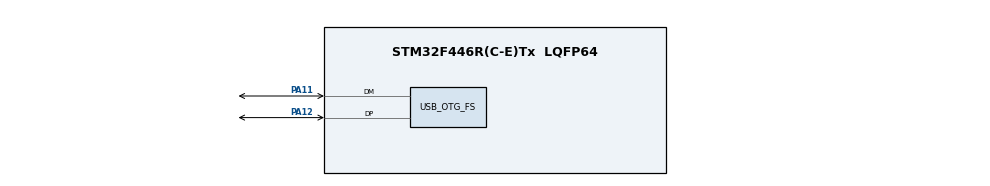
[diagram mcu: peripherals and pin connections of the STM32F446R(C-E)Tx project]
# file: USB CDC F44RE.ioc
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Mcu.Family=STM32F4
Mcu.Name=STM32F446R(C-E)Tx
Mcu.Package=LQFP64
NVIC.OTG_FS_IRQn=true\:0\:0\:false\:false\:true\:false\:true\:true
NVIC.PriorityGroup=NVIC_PRIORITYGROUP_4
NVIC.RCC_IRQn=true\:0\:0\:false\:false\:true\:true\:false\:true
PA11.Mode=Device_Only
PA11.Signal=USB_OTG_FS_DM
PA12.Mode=Device_Only
PA12.Signal=USB_OTG_FS_DP
PC14-OSC32_IN.Mode=LSE-External-Oscillator
PC14-OSC32_IN.Signal=RCC_OSC32_IN
PC15-OSC32_OUT.Mode=LSE-External-Oscillator
PC15-OSC32_OUT.Signal=RCC_OSC32_OUT
PH0-OSC_IN.Mode=HSE-External-Oscillator
PH0-OSC_IN.Signal=RCC_OSC_IN
PH1-OSC_OUT.Mode=HSE-External-Oscillator
PH1-OSC_OUT.Signal=RCC_OSC_OUT
ProjectManager.HeapSize=0x200
ProjectManager.StackSize=0x400
ProjectManager.TargetToolchain=STM32CubeIDE
RCC.AHBFreq_Value=72000000
RCC.APB1CLKDivider=RCC_HCLK_DIV2
RCC.APB1Freq_Value=36000000
RCC.APB1TimFreq_Value=72000000
RCC.APB2Freq_Value=72000000
RCC.APB2TimFreq_Value=72000000
RCC.CortexFreq_Value=72000000
RCC.HCLKFreq_Value=72000000
RCC.HSE_VALUE=8000000
RCC.PLLM=4
RCC.PLLN=72
RCC.PLLQ=3
RCC.SYSCLKFreq_VALUE=72000000
RCC.SYSCLKSource=RCC_SYSCLKSOURCE_PLLCLK
RCC.USBFreq_Value=48000000
RCC.VCOOutputFreq_Value=144000000
USB_DEVICE.CLASS_NAME_FS=CDC
USB_DEVICE.VirtualMode-CDC_FS=Cdc
USB_DEVICE.VirtualModeFS=Cdc_FS
USB_OTG_FS.VirtualMode=Device_Only
VP_USB_DEVICE_VS_USB_DEVICE_CDC_FS.Mode=CDC_FS
board=custom

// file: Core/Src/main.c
/* USER CODE BEGIN Header */
/**
  ******************************************************************************
  * @file           : main.c
  * @brief          : Main program body
  ******************************************************************************
  * @attention
  *
  * Copyright (c) 2023 STMicroelectronics.
  * All rights reserved.
  *
  * This software is licensed under terms that can be found in the LICENSE file
  * in the root directory of this software component.
  * If no LICENSE file comes with this software, it is provided AS-IS.
  *
  ******************************************************************************
  */
/* USER CODE END Header */
#include "main.h"
#include "usb_device.h"

/* USER CODE BEGIN Includes */
#include "usbd_cdc_if.h"
/* USER CODE END Includes */

/* USER CODE BEGIN PV */
	uint16_t uresult=0;
/* USER CODE END PV */

void SystemClock_Config(void);
static void MX_GPIO_Init(void);

int main(void)
{
  /* USER CODE BEGIN 1 */
	char *msg = "\nHello Duta'h";
  /* USER CODE END 1 */

  /* MCU Configuration--------------------------------------------------------*/

  /* Reset of all peripherals, Initializes the Flash interface and the Systick. */
  HAL_Init();

  /* Configure the system clock */
  SystemClock_Config();

  /* Initialize all configured peripherals */
  MX_GPIO_Init();
  MX_USB_DEVICE_Init();

  /* Infinite loop */
  /* USER CODE BEGIN WHILE */
  while (1)
  {
	  uresult = CDC_Transmit_FS(msg, strlen(msg));
	  HAL_Delay(1000);
    /* USER CODE END WHILE */

  }
}

void SystemClock_Config(void)
{
  RCC_OscInitTypeDef RCC_OscInitStruct = {0};
  RCC_ClkInitTypeDef RCC_ClkInitStruct = {0};

  /** Configure the main internal regulator output voltage
  */
  __HAL_RCC_PWR_CLK_ENABLE();
  __HAL_PWR_VOLTAGESCALING_CONFIG(PWR_REGULATOR_VOLTAGE_SCALE1);

  /** Initializes the RCC Oscillators according to the specified parameters
  * in the RCC_OscInitTypeDef structure.
  */
  RCC_OscInitStruct.OscillatorType = RCC_OSCILLATORTYPE_HSE;
  RCC_OscInitStruct.HSEState = RCC_HSE_ON;
  RCC_OscInitStruct.PLL.PLLState = RCC_PLL_ON;
  RCC_OscInitStruct.PLL.PLLSource = RCC_PLLSOURCE_HSE;
  RCC_OscInitStruct.PLL.PLLM = 4;
  RCC_OscInitStruct.PLL.PLLN = 168;
  RCC_OscInitStruct.PLL.PLLP = RCC_PLLP_DIV2;
  RCC_OscInitStruct.PLL.PLLQ = 7;
  RCC_OscInitStruct.PLL.PLLR = 2;
  if (HAL_RCC_OscConfig(&RCC_OscInitStruct) != HAL_OK)
  {
    Error_Handler();
  }

  /** Initializes the CPU, AHB and APB buses clocks
  */
  RCC_ClkInitStruct.ClockType = RCC_CLOCKTYPE_HCLK|RCC_CLOCKTYPE_SYSCLK
                              |RCC_CLOCKTYPE_PCLK1|RCC_CLOCKTYPE_PCLK2;
  RCC_ClkInitStruct.SYSCLKSource = RCC_SYSCLKSOURCE_PLLCLK;
  RCC_ClkInitStruct.AHBCLKDivider = RCC_SYSCLK_DIV1;
  RCC_ClkInitStruct.APB1CLKDivider = RCC_HCLK_DIV4;
  RCC_ClkInitStruct.APB2CLKDivider = RCC_HCLK_DIV2;

  if (HAL_RCC_ClockConfig(&RCC_ClkInitStruct, FLASH_LATENCY_5) != HAL_OK)
  {
    Error_Handler();
  }
}

static void MX_GPIO_Init(void)
{

  /* GPIO Ports Clock Enable */
  __HAL_RCC_GPIOC_CLK_ENABLE();
  __HAL_RCC_GPIOH_CLK_ENABLE();
  __HAL_RCC_GPIOA_CLK_ENABLE();

}

void Error_Handler(void)
{
  __disable_irq();
  while (1)
  {
  }
}
